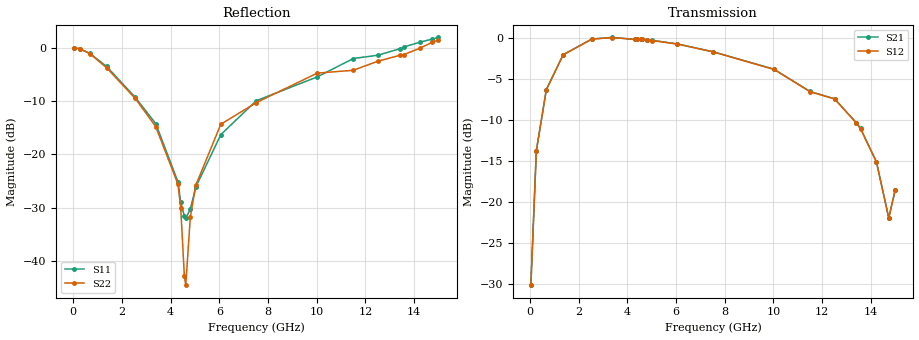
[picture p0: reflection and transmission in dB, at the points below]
! VJ1111D1R2BXR
! DATE 03/08/2022  10:36
! CAPACITORS MOUNTED IN SERIES ON 25 MIL THICK MICROSTRIP SUBSTRATE
# GHz  S  MA  R  50.00
!  FREQ  S11M  S11A  S21M  S21A  S12M  S12A  S22M  S22A
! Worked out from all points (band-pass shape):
!   801 points, 40 MHz to 15 GHz, reference 50 ohm
!   highest |S21| = 0.04 dB at 3.387 GHz (marker M1); lowest = -30.1 dB at 40 MHz (marker M2)
!   |S21| within 3 dB of the highest: 1.144 GHz to 9.193 GHz (8.048 GHz wide, 156 % of centre)
!   lowest |S11| = -32.0 dB at 4.622 GHz (marker M3), VSWR 1.05, Z = 47.6 - j0.259 ohm
!   |S11| at or under -10 dB: 2.661 GHz to 7.502 GHz (4.841 GHz wide, 95.3 % of centre)
!   |S22| runs from -45.5 to 1.5 dB; largest |S21 - S12| = 0.0056
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0.04  0.9963 -1.8  0.03129 87.8  0.03129 88.6  1.005 -1.8
0.2644  0.9778 -11.4  0.2054 79.0  0.2053 78.9  0.9833 -11.4
0.6758  0.8891 -27.9  0.4838 63.5  0.4832 63.5  0.8836 -27.9
1.3677  0.6708 -48.9  0.7881 43.7  0.7862 43.7  0.6518 -50.5
2.5458  0.3436 -72.2  0.9817 23.4  0.9789 23.5  0.3355 -75.8
3.3873  0.1951 -86.9  1.004 14.6  1.002 14.7  0.1829 -89.9
4.3036  0.05527 -133.8  0.9765 8.1  0.9748 8.2  0.05251 -109.1
4.4158  0.03553 -141.9  0.9781 7.9  0.9772 7.9  0.03133 -128.5
4.5654  0.02641 -160.7  0.9798 6.7  0.9786 6.8  0.007188 -169.1
4.6215  0.02512 -173.8  0.9789 6.3  0.9766 6.4  0.005962 120.5
4.8085  0.03083 142.8  0.972 5.0  0.9702 5.1  0.02577 73.8
5.0329  0.04949 116.6  0.963 3.4  0.9604 3.6  0.0514 69.3
6.0614  0.1536 87.7  0.9156 -3.6  0.914 -3.3  0.1922 64.3
7.52  0.3194 69.9  0.8212 -11.2  0.82 -11.1  0.3066 56.4
10.0258  0.5344 53.5  0.6434 -24.4  0.6406 -24.2  0.5795 41.9
11.5031  0.7938 43.7  0.471 -31.5  0.4696 -31.2  0.6158 22.8
12.5129  0.8528 30.3  0.425 -37.8  0.424 -37.5  0.7493 32.8
13.4105  0.98 23.0  0.3032 -45.6  0.3026 -45.3  0.8506 27.3
13.5788  1.019 -156.4  0.2805 -46.9  0.2795 -46.6  0.8646 -155.5
14.2333  1.129 -156.7  0.1759 -49.5  0.1752 -49.1  0.9908 -166.7
14.7382  1.207 -163.1  0.08019 -15.1  0.07994 -14.5  1.126 -174.9
15  1.253 -170.1  0.1183 31.9  0.1177 32.2  1.185 -178.5
